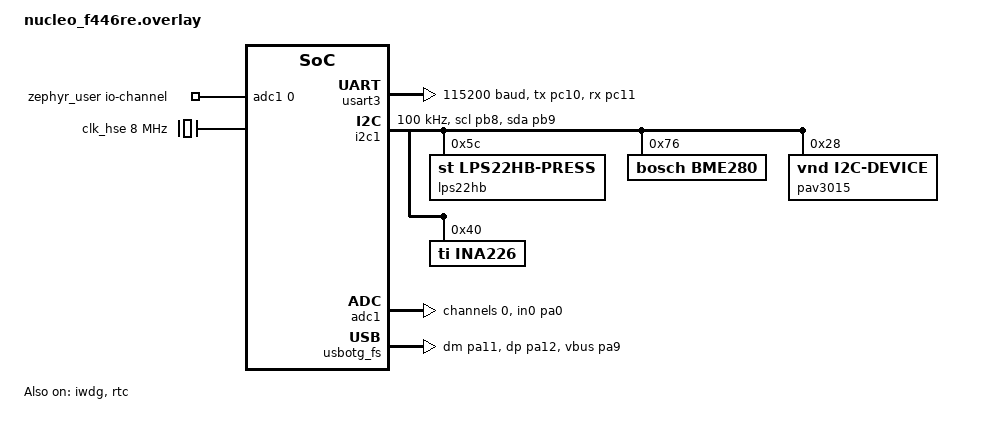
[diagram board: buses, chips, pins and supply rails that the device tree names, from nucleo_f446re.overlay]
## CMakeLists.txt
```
cmake_minimum_required(VERSION 3.20.0)

find_package(Zephyr REQUIRED HINTS $ENV{ZEPHYR_BASE})
project(medical_firmware)

zephyr_cc_option(-Wno-deprecated-declarations -Wno-deprecated)

target_include_directories(app PRIVATE
    include
    include/Power_Management_System
    include/RTOS_Command_based_thread_system
    include/Smart_Battery_System
)

# Sources moved into subfolders
file(GLOB PMS_SRCS      CONFIGURE_DEPENDS ${CMAKE_CURRENT_SOURCE_DIR}/src/Power_Management_System/*.cpp)
file(GLOB BATT_SRCS     CONFIGURE_DEPENDS ${CMAKE_CURRENT_SOURCE_DIR}/src/Smart_Battery_System/*.cpp)
file(GLOB RTOS_CMD_SRCS CONFIGURE_DEPENDS ${CMAKE_CURRENT_SOURCE_DIR}/src/RTOS_Command_based_thread_system/*.cpp)
file(GLOB USB_CDC_SHELL_SRCS CONFIGURE_DEPENDS ${CMAKE_CURRENT_SOURCE_DIR}/src/USB_CDC_SHELL/*.cpp)
file(GLOB FAULT_TOLERANT_I2C_SRCS CONFIGURE_DEPENDS ${CMAKE_CURRENT_SOURCE_DIR}/src/Fault_Tolerant_I2C/*.cpp)

target_sources(app PRIVATE
    src/main.cpp
    ${RTOS_CMD_SRCS}
    src/RTOS_Synchronization_Layer.cpp
    src/Device_State_Machine+Watchdog.cpp
    ${FAULT_TOLERANT_I2C_SRCS}
    src/Persistent_Configuration_System.cpp
    ${PMS_SRCS}
    ${BATT_SRCS}
    src/Static_Memory+MISRA_Compliance_Layer.cpp
    ${USB_CDC_SHELL_SRCS}
)

if(CONFIG_BOARD_MPS2_AN386)
    target_sources(app PRIVATE
        src/qemu_sensor_mocks.c
    )
endif()

target_compile_options(app PRIVATE
    -Wall
    -Wextra
    -Werror
    -Wno-pedantic
    -Wno-variadic-macros
    -Wno-vla
    -Wno-missing-field-initializers
    -Wno-unused-parameter
)

if(CONFIG_COVERAGE)
    target_compile_options(app PRIVATE --coverage -O0)
    target_link_options(app PRIVATE --coverage)
endif()
```

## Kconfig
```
source "Kconfig.zephyr"

config LOG_PREEMPTION_DELAY
    bool "Enable logging for thread pre-emption cycle delays"
    default n
    help
      Enables the LOG_INF statements that print the cycle delay between
      command queue insertion and thread dispatch.

config SOC_MPS2_AN386
    bool
    select HAS_PM
      
config LOG_EXECUTION_CYCLES
    bool "Enable logging for command execution cycle times"
    default n
    help
      Enables the LOG_INF statements inside the CycleProfiler that print
      how many CPU cycles it took to execute a command.
```

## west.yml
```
manifest:
  remotes:
    - name: zephyrproject-rtos
      url-base: https://github.com/zephyrproject-rtos
  projects:
    - name: zephyr
      remote: zephyrproject-rtos
      revision: v4.4.0        # was: main
      import: true
  self:
    path: custom_app
```

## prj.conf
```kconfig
CONFIG_CPP=y
CONFIG_STD_CPP20=y
CONFIG_HEAP_MEM_POOL_SIZE=0
CONFIG_STACK_CANARIES=y

CONFIG_TEST_RANDOM_GENERATOR=y

CONFIG_CONSOLE=y
CONFIG_ASSERT=y
CONFIG_UART_LOG_LEVEL_DBG=y
CONFIG_SHELL_BACKEND_SERIAL=n

CONFIG_PM_DEVICE=y
CONFIG_SHELL=y
CONFIG_SHELL_VT100_COMMANDS=n
CONFIG_FLASH=y
CONFIG_FLASH_MAP=y
CONFIG_FLASH_PAGE_LAYOUT=y
CONFIG_FCB=y
CONFIG_ARM_MPU=y
CONFIG_HW_STACK_PROTECTION=y
CONFIG_MPU_ALLOW_FLASH_WRITE=y

CONFIG_THREAD_NAME=y
CONFIG_THREAD_RUNTIME_STATS=y
CONFIG_TRACING=y
CONFIG_TRACING_USER=y
CONFIG_TRACING_CTF=n
CONFIG_TRACING_BACKEND_UART=n
CONFIG_TRACING_ASYNC=n
CONFIG_TRACING_SYSCALL=n
CONFIG_LOG_BACKEND_FORMAT_TIMESTAMP=y
CONFIG_LOG_BACKEND_SHOW_COLOR=n
CONFIG_LOG_PROCESS_THREAD=y
CONFIG_LOG_MODE_DEFERRED=y
CONFIG_LOG_PROCESS_TRIGGER_THRESHOLD=1
CONFIG_LOG_PROCESS_THREAD_STARTUP_DELAY_MS=0
CONFIG_LOG_PROCESS_THREAD_SLEEP_MS=10

CONFIG_RTC=y
CONFIG_RTC_ALARM=y
CONFIG_LOG=y
CONFIG_LOG_BACKEND_UART=y
CONFIG_PRINTK=y

CONFIG_REQUIRES_FULL_LIBCPP=y
CONFIG_GLIBCXX_LIBCPP=y

CONFIG_WATCHDOG=y
CONFIG_I2C=y
CONFIG_SENSOR=y
CONFIG_REBOOT=y
CONFIG_ADC=y
CONFIG_CBPRINTF_FP_SUPPORT=y
CONFIG_NEWLIB_LIBC=n
CONFIG_NEWLIB_LIBC_MIN_REQUIRED_HEAP_SIZE=0
CONFIG_TIMESLICING=y
CONFIG_LOG_PREEMPTION_DELAY=y
CONFIG_LOG_EXECUTION_CYCLES=n
CONFIG_THREAD_STACK_INFO=y
```

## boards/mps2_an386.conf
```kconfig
# boards/qemu_cortex_m3.conf

# 1. Simulated Flash and NVS
CONFIG_FLASH=y
CONFIG_FLASH_SIMULATOR=y
CONFIG_FLASH_PAGE_LAYOUT=y
CONFIG_FLASH_MAP=y
CONFIG_NVS=y

# 2. General Subsystems
CONFIG_REBOOT=y
CONFIG_COUNTER=y
CONFIG_I2C=y
CONFIG_TEST_RANDOM_GENERATOR=y
CONFIG_WATCHDOG=y

# 3. Standard Console & C++ (Required for QEMU output)
CONFIG_CPP=y
CONFIG_STD_CPP20=y
CONFIG_SERIAL=y
CONFIG_CONSOLE=y
CONFIG_UART_CONSOLE=y
CONFIG_PRINTK=y
CONFIG_LOG_BUFFER_SIZE=4096
CONFIG_LOG_MODE_DEFERRED=y
CONFIG_LOG_PROCESS_THREAD=y
CONFIG_LOG_PROCESS_THREAD_STACK_SIZE=768
CONFIG_ISR_STACK_SIZE=512
CONFIG_SHELL_STACK_SIZE=512
CONFIG_IDLE_STACK_SIZE=128
CONFIG_EMUL=y
CONFIG_I2C_EMUL=y
CONFIG_ADC_EMUL=y
CONFIG_FLASH_SIMULATOR=y
CONFIG_FLASH_SIMULATOR_UNALIGNED_READ=y
CONFIG_INA226=y
CONFIG_SEMIHOST=y
CONFIG_PERCEPIO_TRACERECORDER=y
CONFIG_PERCEPIO_TRC_CFG_STREAM_PORT_RTT=n
CONFIG_PERCEPIO_TRC_CFG_STREAM_PORT_RINGBUFFER=y

CONFIG_LOG_BACKEND_XTENSA_SIM=n 
CONFIG_LOG_TIMESTAMP_64BIT=y
CONFIG_LOG_DEFAULT_LEVEL=3
CONFIG_LOG_BACKEND_UART=y
CONFIG_LOG_PRINTK=n
CONFIG_SYSTEM_WORKQUEUE_STACK_SIZE=384
CONFIG_SYS_CLOCK_TICKS_PER_SEC=1000
```

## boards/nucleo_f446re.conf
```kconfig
CONFIG_USB_CDC_ACM=y
CONFIG_USB_DEVICE_STACK=y
CONFIG_USB_DEVICE_INITIALIZE_AT_BOOT=n
CONFIG_UART_INTERRUPT_DRIVEN=y
CONFIG_UART_LINE_CTRL=y
CONFIG_CBPRINTF_FP_SUPPORT=y

CONFIG_USB_DEVICE_VID=0x0483
CONFIG_USB_DEVICE_PID=0x5740
CONFIG_USB_DEVICE_PRODUCT="Medical Firmware"
CONFIG_USB_DEVICE_MANUFACTURER="STM Microelectronics"
CONFIG_LOG_MODE_IMMEDIATE=n
CONFIG_LOG_BUFFER_SIZE=8192
CONFIG_SENSOR=y
CONFIG_BME280=y
CONFIG_LPS22HB=y
CONFIG_UART_CONSOLE=y

CONFIG_PERCEPIO_TRACERECORDER=n
CONFIG_PERCEPIO_TRC_START_MODE_START=n
CONFIG_PERCEPIO_TRC_CFG_STREAM_PORT_ITM=n
CONFIG_SEGGER_SYSTEMVIEW=n
CONFIG_USE_SEGGER_RTT=y
CONFIG_SEGGER_RTT_BUFFER_SIZE_UP=4096
CONFIG_LOG_BACKEND_SWO=n
CONFIG_SYS_CLOCK_EXISTS=y
CONFIG_STM32_LPTIM_TIMER=y
CONFIG_PM=y
CONFIG_PM_POLICY_DEVICE_CONSTRAINTS=y
CONFIG_SIZE_OPTIMIZATIONS=y
CONFIG_RTC_STM32=y
CONFIG_DEBUG_THREAD_INFO=y
CONFIG_INIT_STACKS=y
CONFIG_STACK_USAGE=y
CONFIG_ISR_STACK_SIZE=4096
CONFIG_COUNTER=n
CONFIG_GPIO=y
CONFIG_IDLE_STACK_SIZE=1024
CONFIG_PM_DEVICE_RUNTIME=n
CONFIG_PM_DEVICE_SYSTEM_MANAGED=n
CONFIG_DEBUG=n
CONFIG_SERIAL=y
CONFIG_ADC_STM32=y
CONFIG_LOG_PRINTK=y
```

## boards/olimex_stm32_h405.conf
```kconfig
# boards/olimex_stm32_h405.conf
# QEMU-safe configuration for olimex_stm32_h405.
# Purpose: run application/RTOS logic without STM32 RCC-dependent hardware drivers.

CONFIG_CPP=y
CONFIG_STD_CPP20=y

# QEMU output is through direct ARM semihosting probe.
CONFIG_SERIAL=n
CONFIG_CONSOLE=n
CONFIG_UART_CONSOLE=n
CONFIG_LOG=n
CONFIG_LOG_BACKEND_UART=n
CONFIG_PRINTK=y
CONFIG_BOOT_BANNER=n

# Disable shell/USB/UART backend paths.
CONFIG_USB_DEVICE_STACK=n
CONFIG_SHELL=n
CONFIG_SHELL_BACKEND_SERIAL=n

# Disable STM32 hardware drivers that depend on RCC/clock-control.
CONFIG_CLOCK_CONTROL=n
CONFIG_GPIO=n
CONFIG_I2C=n
CONFIG_SENSOR=n
CONFIG_WATCHDOG=n
CONFIG_COUNTER=n
CONFIG_COUNTER_RTC_STM32=n
CONFIG_FLASH=n
CONFIG_FLASH_PAGE_LAYOUT=n
CONFIG_NVS=n
CONFIG_PM=n
CONFIG_PM_DEVICE=n

# Disable entropy/RNG path that still tries to use the STM32 clock device.
CONFIG_ENTROPY_GENERATOR=n
CONFIG_ENTROPY_STM32_RNG=n
CONFIG_TEST_RANDOM_GENERATOR=y

CONFIG_REBOOT=y

CONFIG_THREAD_NAME=y
CONFIG_THREAD_ANALYZER=n
CONFIG_THREAD_ANALYZER_AUTO=n
CONFIG_THREAD_ANALYZER_RUN_UNLOCKED=n
CONFIG_RTC=n
```

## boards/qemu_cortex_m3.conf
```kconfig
# boards/qemu_cortex_m3.conf

# 1. Simulated Flash and NVS
CONFIG_FLASH=y
CONFIG_FLASH_SIMULATOR=y
CONFIG_FLASH_PAGE_LAYOUT=y
CONFIG_FLASH_MAP=y
CONFIG_NVS=y

# 2. General Subsystems
CONFIG_REBOOT=y
CONFIG_COUNTER=y
CONFIG_I2C=y
CONFIG_TEST_RANDOM_GENERATOR=y
CONFIG_WATCHDOG=y

# 3. Standard Console & C++ (Required for QEMU output)
CONFIG_CPP=y
CONFIG_STD_CPP20=y
CONFIG_SERIAL=y
CONFIG_CONSOLE=y
CONFIG_UART_CONSOLE=y
CONFIG_PRINTK=y
CONFIG_LOG_BUFFER_SIZE=8192
CONFIG_LOG_MODE_IMMEDIATE=y
CONFIG_HW_STACK_PROTECTION=y
CONFIG_ISR_STACK_SIZE=512
CONFIG_SHELL_STACK_SIZE=1024

CONFIG_SEMIHOST=y
CONFIG_PERCEPIO_TRACERECORDER=y
CONFIG_PERCEPIO_TRC_START_MODE_START=y
CONFIG_PERCEPIO_TRC_CFG_STREAM_PORT_ZEPHYR_SEMIHOST=y

CONFIG_LOG_BACKEND_XTENSA_SIM=n 
```

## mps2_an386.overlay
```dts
#include <zephyr/dt-bindings/adc/adc.h>
/delete-node/ &storage_partition;

/ {
    chosen {
        zephyr,console = &uart0;
    };
    
    zephyr_user: zephyr,user {
        io-channels = <&adc_emul0 0>;
    };

    adc_emul0: adc_emul {
        compatible = "zephyr,adc-emul";
        nchannels = <1>;
        #io-channel-cells = <1>;
        #address-cells = <1>;
        #size-cells = <0>;
        status = "okay";
        ref-internal-mv = <3300>;    
        
        channel@0 {
            reg = <0>;
            zephyr,gain = "ADC_GAIN_1";
            zephyr,reference = "ADC_REF_INTERNAL";
            zephyr,acquisition-time = <ADC_ACQ_TIME_DEFAULT>;
            zephyr,resolution = <12>;
        };
    };
    
    aliases {
        cdc-acm-uart0 = &uart1; 
        watchdog0 = &wdog0;
        rtc0 = &rtc_emul0;
        uart-hardware = &uart0;
        i2c1 = &i2c_emul0;
    };
    
    rtc_emul0: rtc {
        compatible = "zephyr,rtc-emul";
        status = "okay";
        alarms-count = <2>;
    };
    
    /* The Emulator Controller */
    i2c_emul0: i2c_emul@50010000 {
    compatible = "zephyr,i2c-emul-controller";
    reg = <0x50010000 0x1000>;
    clock-frequency = <100000>;
    status = "okay";

    #address-cells = <1>;
    #size-cells = <0>;

    lps22hb: lps22hb@5c {
        compatible = "st,lps22hb-press";
        reg = <0x5c>;
        status = "okay";
    };

    bme280: bme280@76 {
        compatible = "bosch,bme280";
        reg = <0x76>;
        status = "okay";
    };

    ina226: ina226@40 {
        compatible = "ti,ina226";
        reg = <0x40>;
        rshunt-micro-ohms = <100000>;
        current-lsb-microamps = <25>;
        status = "okay";
    };

    pav3015: pav3015@28 {
        compatible = "vnd,i2c-device";
        reg = <0x28>;
        status = "disabled";
    };
    };

    /* Simulated Flash Drive for NVS */
    sim_flash: sim_flash@50000000 {
        compatible = "zephyr,sim-flash";
        /* Expand total simulated flash to 512 KB to fit the Nucleo layout */
        reg = <0x50000000 0x80000>; 
        #address-cells = <1>;
        #size-cells = <1>;
        erase-value = <0xff>;

        my_sim_flash0: flash_sim@0 {
            status = "okay";
            compatible = "soc-nv-flash";
            erase-block-size = <131072>; 
            
            /* CHANGE THIS TO 1: Allows 1-byte and 2-byte FCB writes to succeed */
            write-block-size = <1>; 
            
            reg = <0x00000000 0x80000>;

            partitions {
                compatible = "fixed-partitions";
                #address-cells = <1>;
                #size-cells = <1>;

                code_partition: partition@0 {
                    label = "image-0";
                    reg = <0x00000000 0x00040000>;
                };

                storage_partition: partition@40000 {
                    label = "storage";
                    reg = <0x00040000 0x00040000>;
                };
            };
        };
    };
};
&uart0 {
    status = "okay";
};

&uart1 {
        status = "okay";
};
```

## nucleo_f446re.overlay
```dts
#include <zephyr/dt-bindings/pinctrl/stm32-pinctrl.h>

/ {
    chosen {
        /* Route Zephyr system logs and console to the USB Virtual COM port */
        zephyr,console = &usart3;
        zephyr,shell-uart = &usart3;
        zephyr,code-partition = &code_partition;
        /delete-property/ zephyr,lpm-timer;
        /delete-property/ zephyr,cortex-m-idle-timer;
    };

    aliases {
        cdc-acm-uart0 = &cdc_acm_uart0;
        rtc0 = &rtc;
    };

    zephyr_user: zephyr,user {
        io-channels = <&adc1 0>;
    };

    cpus {
        cpu0: cpu@0 {
            cpu-power-states = <&stop0>;
        };
    };

    power-states {
        stop0: state0 {
            compatible = "zephyr,power-state";
            power-state-name = "suspend-to-ram";
            min-residency-us = <100000>;
            exit-latency-us = <2000>;
        };
    };
};

/* --- DEDICATED SLEEP PIN STATES ---
 * NOTE: the STM32 pinctrl binding requires ONE pinmux value per node.
 * Multi-pin groups are formed by listing several node phandles in
 * pinctrl-N, not by stacking values inside a single node.
 */
&pinctrl {
    /* FIX: Changed from AF7 to strictly ANALOG to prevent UART leakage */
    usart3_tx_sleep: usart3_tx_sleep {
        pinmux = <STM32_PINMUX('C', 10, ANALOG)>;
    };
    usart3_rx_sleep: usart3_rx_sleep {
        pinmux = <STM32_PINMUX('C', 11, ANALOG)>;
    };

    /* FIX: Changed from AF4 to strictly ANALOG to prevent I2C pull-up leakage */
    i2c1_scl_sleep: i2c1_scl_sleep {
        pinmux = <STM32_PINMUX('B', 8, ANALOG)>;
    };
    i2c1_sda_sleep: i2c1_sda_sleep {
        pinmux = <STM32_PINMUX('B', 9, ANALOG)>;
    };

    adc1_in0_sleep: adc1_in0_sleep {
        pinmux = <STM32_PINMUX('A', 0, ANALOG)>;
    };

    usb_otg_fs_vbus_sleep: usb_otg_fs_vbus_sleep {
        pinmux = <STM32_PINMUX('A', 9, ANALOG)>;
    };
};

/* Disable ST-Link UART for Standalone Mode */
&usart3 {
    status = "okay";
    current-speed = <115200>;
    pinctrl-0 = <&usart3_tx_pc10 &usart3_rx_pc11>;
    pinctrl-1 = <&usart3_tx_sleep &usart3_rx_sleep>;
    pinctrl-names = "default", "sleep";
};

/* Explicitly disable unused buses to prevent phantom PM warnings */
&i2c2 { status = "disabled"; };
&i2c3 { status = "disabled"; };

&i2c1 {
    status = "okay";
    pinctrl-0 = <&i2c1_scl_pb8 &i2c1_sda_pb9>;
    pinctrl-1 = <&i2c1_scl_sleep &i2c1_sda_sleep>;
    pinctrl-names = "default", "sleep";
    clock-frequency = <I2C_BITRATE_STANDARD>;

    lps22hb: lps22hb@5c {
        compatible = "st,lps22hb-press";
        reg = <0x5c>;
        status = "okay";
    };
    bme280: bme280@76 {
        compatible = "bosch,bme280";
        reg = <0x76>;
        status = "okay";
    };
    pav3015: pav3015@28 {
        compatible = "vnd,i2c-device";
        reg = <0x28>;
        status = "okay";
    };
    ina226: ina226@40 {
        compatible = "ti,ina226";
        reg = <0x40>;
        rshunt-micro-ohms = <100000>;
        current-lsb-microamps = <25>;
        status = "okay";
    };
};

&adc1 {
    #address-cells = <1>;
    #size-cells = <0>;
    pinctrl-0 = <&adc1_in0_pa0>;
    pinctrl-1 = <&adc1_in0_sleep>;
    pinctrl-names = "default", "sleep";
    st,adc-prescaler = <2>;
    status = "okay";

    channel@0 {
        reg = <0>;
        zephyr,gain = "ADC_GAIN_1";
        zephyr,reference = "ADC_REF_INTERNAL";
        zephyr,acquisition-time = <ADC_ACQ_TIME_DEFAULT>;
        zephyr,resolution = <12>;
    };
};

&gpioa { status = "okay"; };
&gpioc { status = "okay"; };
&iwdg { status = "okay"; };
&usart2 { status = "disabled"; };
&clk_lse { status = "okay"; };

&rtc {
    status = "okay";
    clocks = <&rcc STM32_CLOCK_BUS_APB1 0x10000000>,
             <&rcc STM32_SRC_LSE RTC_SEL(1)>;
    wakeup-source;
};

&clk_hse {
    clock-frequency = <DT_FREQ_M(8)>;
    hse-bypass;
    status = "okay";
};

&pll {
    clocks = <&clk_hse>;
    div-m = <8>;
    mul-n = <384>;
    div-p = <4>;
    div-q = <8>;
    status = "okay";
};

&rcc {
    clocks = <&pll>;
    clock-frequency = <DT_FREQ_M(96)>;
    ahb-prescaler = <1>;
    apb1-prescaler = <4>;
    apb2-prescaler = <2>;
};

&usbotg_fs {
    status = "okay";
    pinctrl-0 = <&usb_otg_fs_dm_pa11 &usb_otg_fs_dp_pa12 &usb_otg_fs_vbus_pa9>;
    /* Only VBUS uses pinctrl sleep. DM/DP left out to allow C++ to force Output Low */
    pinctrl-1 = <&usb_otg_fs_vbus_sleep>;
    pinctrl-names = "default", "sleep";

    cdc_acm_uart0: cdc_acm_uart0 {
        compatible = "zephyr,cdc-acm-uart";
        label = "CDC_ACM_0";
        tx-fifo-size = <2048>;
   	rx-fifo-size = <2048>; 
    };
};

/delete-node/ &boot_partition;
/delete-node/ &slot0_partition;
/delete-node/ &slot1_partition;
/delete-node/ &scratch_partition;
/delete-node/ &storage_partition;

&flash0 {
    partitions {
        compatible = "fixed-partitions";
        #address-cells = <1>;
        #size-cells = <1>;

        code_partition: partition@0 {
            label = "image-0";
            reg = <0x00000000 0x00040000>;
        };

        storage_partition: partition@40000 {
            label = "storage";
            reg = <0x00040000 0x00040000>;
        };
    };
};
```

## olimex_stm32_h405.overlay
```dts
/* olimex_stm32_h405.overlay */

/ {
    chosen {
        zephyr,console = &usart2;
        zephyr,shell-uart = &usart2;
    };

    aliases {
        serial0 = &usart2;

        /*
         * Your USB_CDC_Virtual_COM_Shell_Interface.cpp uses:
         * DEVICE_DT_GET(DT_ALIAS(cdc_acm_uart0))
         *
         * USB is disabled in QEMU, so map this alias to USART2.
         */
        cdc-acm-uart0 = &usart2;
    };
};

/*
 * QEMU-safe clock configuration.
 * Use HSI instead of external HSE/PLL.
 */
&clk_hsi {
    status = "okay";
};

&clk_hse {
    status = "disabled";
};

&pll {
    status = "disabled";
};

&rcc {
    clocks = <&clk_hsi>;
    clock-frequency = <16000000>;
    ahb-prescaler = <1>;
    apb1-prescaler = <1>;
    apb2-prescaler = <1>;
};

&usart2 {
    status = "okay";
    current-speed = <115200>;
    pinctrl-0 = <&usart2_tx_pa2 &usart2_rx_pa3>;
    pinctrl-names = "default";
};

&usbotg_fs {
    status = "disabled";
};

/*
 * Keep I2C enabled in DTS if your full firmware expects i2c1 device.
 * Your I2CManager already mocks reads/writes for CONFIG_BOARD_OLIMEX_STM32_H405.
 */
&i2c1 {
    status = "okay";
    pinctrl-0 = <&i2c1_scl_pb6 &i2c1_sda_pb7>;
    pinctrl-names = "default";
};

&rtc {
    status = "okay";
};

&iwdg {
    status = "okay";
};

/*
 * Required by Persistent_Configuration_System.cpp:
 * DT_NODELABEL(storage_partition)
 */
&flash0 {
    partitions {
        compatible = "fixed-partitions";
        #address-cells = <1>;
        #size-cells = <1>;

        storage_partition: partition@E0000 {
            label = "storage";
            reg = <0x000E0000 0x00020000>;
        };
    };
};

/*
 * QEMU mode:
 * Disable STM32 EXTI and RNG/entropy nodes because they depend on
 * stm32_clock_control_init / RCC, which hangs under olimex-stm32-h405 QEMU.
 */
&exti {
    status = "disabled";
};

&rng {
    status = "disabled";
};
```

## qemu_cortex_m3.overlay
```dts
/ {
    aliases {
        cdc-acm-uart0 = &uart0;
    };

    /* The Golden Stub: We map all missing hardware to the I2C test driver */
    i2c1: fake_i2c@40001000 {
        compatible = "vnd,i2c";
        reg = <0x40001000 0x1000>;
        status = "okay";
        #address-cells = <1>;
        #size-cells = <0>;
    };

    iwdg: fake_watchdog@40002000 {
        compatible = "vnd,i2c";
        reg = <0x40002000 0x1000>;
        status = "okay";
        #address-cells = <1>;
        #size-cells = <0>;
    };

    rtc: fake_rtc@40003000 {
        compatible = "vnd,i2c";
        reg = <0x40003000 0x1000>;
        status = "okay";
        #address-cells = <1>;
        #size-cells = <0>;
    };

    /* Simulated Flash Drive for NVS */
    sim_flash: sim_flash@50000000 {
        compatible = "zephyr,sim-flash";
        reg = <0x50000000 0x8000>;
        #address-cells = <1>;
        #size-cells = <1>;
        erase-value = <0xff>;

        flash_sim0: flash_sim@0 {
            status = "okay";
            compatible = "soc-nv-flash";
            erase-block-size = <1024>;
            write-block-size = <4>;
            reg = <0x00000000 0x8000>;

            partitions {
                compatible = "fixed-partitions";
                #address-cells = <1>;
                #size-cells = <1>;

                storage_partition: partition@6000 {
                    label = "storage";
                    reg = <0x00006000 0x00002000>;
                };
            };
        };
    };
};
```

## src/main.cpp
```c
#include <zephyr/kernel.h>
#include <zephyr/logging/log.h>
#include <zephyr/sys/printk.h>
#ifdef CONFIG_USB_DEVICE_STACK
#include <zephyr/usb/usb_device.h>
#endif
#include <zephyr/drivers/uart.h>
#include <cerrno>

#include "RTOS_Command_Based_Thread_System.h"
#include "RTOS_Synchronization_Layer.h"
#include "Device_State_Machine+Watchdog.h"
#include "Smart_Battery_System.h"
#include "Persistent_Configuration_System.h"
#include "Static_Memory+MISRA_Compliance_Layer.h"
#include "Power_Management_System.h"

#include <zephyr/debug/thread_analyzer.h>
#include <new>
#include <zephyr/sys/atomic.h>

LOG_MODULE_REGISTER(MAIN_OS, LOG_LEVEL_INF);

// Add the external flag at the top with your other externs
extern bool g_usb_connected;

#ifdef CONFIG_USB_DEVICE_STACK
/* Callback to monitor physical USB hardware events */
static void usb_status_cb(enum usb_dc_status_code cb_status, const uint8_t *param) {
    switch (cb_status) {
        case USB_DC_DISCONNECTED:
        case USB_DC_SUSPEND:
            if (g_usb_connected) {
                LOG_WRN("USB Hardware Event: Cable Disconnected");
                g_usb_connected = false;
                
                // Immediately trigger the fault when the physical cable is pulled
                sys_context.triggerFault("USB CDC Cable Disconnected");
            }
            break;
        case USB_DC_CONFIGURED:
            if (!g_usb_connected) {
                LOG_INF("USB Hardware Event: Cable Connected & Configured");
                g_usb_connected = true;
            }
            break;
        default:
            break;
    }
}
#endif

int main(void){
    printk("BOOT\n");
    const struct device *const console_dev  =  DEVICE_DT_GET(DT_CHOSEN(zephyr_console));
    
    if (device_is_ready(console_dev)) {
#ifdef CONFIG_USB_DEVICE_STACK
        /* Initialize USB Subsystem ONCE globally, attaching our new callback */
        int usb_err = usb_enable(usb_status_cb); // Changed from nullptr
        
        if (usb_err == 0 || usb_err == -EALREADY) {
            uint32_t dtr = 0;
            int timeout = 30; // 3 seconds max wait

            while (!dtr && timeout > 0) {
                // If the hardware callback fired and marked us unplugged, skip the wait
                if (!g_usb_connected) break; 
                
                int ret = uart_line_ctrl_get(console_dev, UART_LINE_CTRL_DTR, &dtr);
                if (ret == -ENOTSUP || ret == -ENOSYS) break; 
                
                k_msleep(100);
                timeout--;
            }
            
            if (dtr) k_msleep(250); 
        } else {
            LOG_ERR("Failed to initialize USB subsystem (err %d)", usb_err);
        }
#endif
    }

    LOG_INF("Command-Based RTOS Booting");

    ConfigStore& config = ConfigStore::getInstance();
    if (config.init()) {
        config.validateEndurance(ConfigKey::ALARM_THRESHOLD_BASE);
        uint16_t infusion_rate = 0;
        if (!config.get(ConfigKey::INFUSION_RATE_BASE, infusion_rate)) {
            LOG_WRN("First boot detected. Setting default infusion rate.");
            config.set(ConfigKey::INFUSION_RATE_BASE, static_cast<uint16_t>(50));
        } else {
            LOG_INF("Loaded Infusion Rate from NVS: %u mL/hr", infusion_rate);
        }
    }
    
    status_work.schedule(K_SECONDS(1));
    return 0;
}
```

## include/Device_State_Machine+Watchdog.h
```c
#pragma once
#include <zephyr/kernel.h>
#include <zephyr/drivers/watchdog.h>
#include "Power_Management_System.h"
/* Global Thread Health Flags (Updated by ALL RTOS Threads) */
extern atomic_t g_producer_alive;
extern atomic_t g_processor_alive;
extern atomic_t g_logger_alive;
extern atomic_t g_hr_prod_alive;
extern atomic_t g_disp_cons_alive;
extern atomic_t g_bms_comm_alive;
extern atomic_t g_batt_mon_alive;
extern atomic_t g_mem_mon_alive;
extern atomic_t g_shell_alive;
extern DeviceContext sys_context;

enum class SystemState {
  INIT,
  RUNNING,
  FAULT,
  SAFE_HALT
};

class WatchdogTimer {
    private:
        const device* wdt_dev;
        int channel_id;
    public:
        WatchdogTimer();
        bool init(uint32_t timeout_ms);
        void feed();
        bool isInitialized() const;
};

class DeviceContext : public IPowerObserver {
    private:
        SystemState current_state;
        WatchdogTimer wdt;
        static bool isLegalTransition(SystemState from, SystemState to);
    public:
        DeviceContext();
        SystemState getState() const;
        bool requestTransition(SystemState next_state);
        bool initWatchdog(uint32_t timeout_ms);
        void feedWatchdog();
        void triggerFault(const char* reason);
        void beforeSleep() override;
        void afterWakeup() override;
        void sleepAborted() override;
};
```

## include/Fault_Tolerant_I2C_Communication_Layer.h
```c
#include <zephyr/drivers/i2c.h>
#include <cstdint>
#include "Static_Memory+MISRA_Compliance_Layer.h"

#pragma once

enum class I2CFault{NONE,NACK,TIMEOUT,BUS_BUSY,ARBITRATION_LOST,DEVICE_NOT_READY};

template <typename T>
struct Result{
    T value;
    I2CFault error;
    bool success;

    static Result<T> Ok(T val){
        return {val,I2CFault::NONE,true};
    }

    static Result<T> Err(I2CFault err){
        return {T(),err,false};
    }

    bool isOk() const {return success; }
    T unwrap() const{ return value; }
};

class I2CStrategy{
  public:
        virtual ~I2CStrategy()=default;
        virtual void executeRecovery(const device* i2c_dev)=0;
};

class RetryStrategy:public I2CStrategy{
  public:
      void executeRecovery(const device* i2c_dev) override;
};

class BusResetStrategy:public I2CStrategy{
  public:
      void executeRecovery(const device* i2c_dev) override;
};

class FailSafeStrategy:public I2CStrategy{
  private:
      uint64_t last_known_good_value=0U;
  public:
      void executeRecovery(const device* i2c_dev) override;
      void updateLastGood(uint64_t val);
      uint64_t getLastGood() const;
};

class I2CManager{
  private:
      const device* i2c_dev;
      RetryStrategy retry_strategy;
      BusResetStrategy reset_strategy;
      FailSafeStrategy failsafe_strategy;
  public:
      explicit I2CManager(const device* dev);
      Result<uint8_t> readRegister(uint16_t sensor_addr,uint8_t reg_addr);
      Result<bool> writeRegister(uint16_t sensor_addr,uint8_t reg_addr,uint8_t val);
      Result<uint16_t> readWord(uint16_t sensor_addr,uint8_t reg_addr);
      Result<bool> writeWord(uint16_t sensor_addr, uint8_t reg_addr, uint16_t val);
      Result<uint32_t> read24Bit(uint16_t sensor_addr,uint8_t reg_addr);
      Result<uint64_t> read64Bit(uint16_t sensor_addr,uint8_t reg_addr);
};

extern I2CManager i2c_manager;
```

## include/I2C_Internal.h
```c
#pragma once

#include <cstdint>
#include "Fault_Tolerant_I2C_Communication_Layer.h"

#ifdef IS_TEST_ENVIRONMENT
extern int g_i2c_force_errno;
#endif

namespace i2c_internal {

/* Map a negative Zephyr driver errno to an I2CFault enum value. */
I2CFault classify_i2c_error(int err);

/* Return true when the fault requires a physical SCL bus reset (TIMEOUT or BUS_BUSY). */
bool is_recoverable_with_bus_reset(I2CFault fault);

/* Classify `err` and execute either `reset_strategy` or `retry_strategy`. */
I2CFault classify_and_recover(int err,
                              const device* i2c_dev,
                              BusResetStrategy& reset_strategy,
                              RetryStrategy& retry_strategy);

/* Store / refresh the value for `key`: resets the reliability score to the maximum, bumps the sample count. */
void update_cache(uint32_t key, uint64_t value, bool calibrated = true);

/* Fallback read: succeeds only for a fresh (<= max_age_ms), reliable (score >= minimum) and calibrated entry,
 * and decays the entry's reliability on every successful use. */
bool get_cached_value(uint32_t key, uint64_t* out_val, uint32_t max_age_ms);

} // namespace i2c_internal
```

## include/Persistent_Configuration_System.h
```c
#pragma once

#include <zephyr/fs/fcb.h>
#include <zephyr/logging/log.h>
#include <zephyr/pm/policy.h>
#include "Power_Management_System.h"
#include <type_traits>
#include <cstdint>
#include <array>

enum class ConfigKey : uint16_t {
    FULL_CHARGE_LOG        = 4,
    DEVICE_ID_BASE         = 100,
    INFUSION_RATE_BASE     = 200,
    ALARM_THRESHOLD_BASE   = 300
};

namespace InfusionDeviceConfig {
    constexpr uint8_t MinSlot = 1;
    constexpr uint8_t MaxSlot = 5;
    constexpr uint8_t NumSlots = 5;

    constexpr uint32_t UnprovisionedId = 0;

    constexpr std::array<uint32_t, NumSlots> DefaultDeviceIds        = {1001, 1002, 1003, 1004, 1005};
    constexpr std::array<uint8_t,  NumSlots> DefaultAlarmThresholds  = {80, 85, 90, 95, 100};

    [[nodiscard]] constexpr bool isValidSlot(uint8_t slot) noexcept {
        return slot >= MinSlot && slot <= MaxSlot;
    }
}

class FlashPowerGuard {
public:
    FlashPowerGuard() {
        pm_policy_state_lock_get(PM_STATE_SUSPEND_TO_RAM, PM_ALL_SUBSTATES);
    }
    ~FlashPowerGuard() {
        pm_policy_state_lock_put(PM_STATE_SUSPEND_TO_RAM, PM_ALL_SUBSTATES);
    }
};

struct FcbRecordHeader {
    ConfigKey key;
    uint16_t length;
};

class ConfigStore {
    private:
        struct fcb fcb_instance;
        struct flash_sector fcb_sectors[2]; // Sectors 6 and 7
        bool initialized;

        static ConfigStore instance;

        ConfigStore();
        ~ConfigStore()=default;

        ConfigStore(const ConfigStore&)=delete;
        ConfigStore& operator=(const ConfigStore&)=delete;

        void seedDefaultDeviceIds();
        void seedDefaultAlarmThresholds();

    public:
        static ConfigStore& getInstance();

        bool init();

        template <typename T>
        bool set(ConfigKey key, const T& value) {
            static_assert(std::is_trivially_copyable<T>::value, "Config data must be trivially copyable");

            if (!initialized){
                return false;
            }

            FlashPowerGuard pm_guard;

            struct fcb_entry loc;
            int rc = fcb_append(&fcb_instance, sizeof(FcbRecordHeader) + sizeof(T), &loc);
            if (rc == -ENOSPC) {
                // Flash area full: rotate (erase oldest sector) and retry once.
                rc = fcb_rotate(&fcb_instance);
                if (rc != 0) {
                    return false;
                }
                rc = fcb_append(&fcb_instance, sizeof(FcbRecordHeader) + sizeof(T), &loc);
            }
            if (rc != 0) {
                return false;
            }

            FcbRecordHeader header = { key, sizeof(T) };
            rc = flash_area_write(fcb_instance.fap, FCB_ENTRY_FA_DATA_OFF(loc), &header, sizeof(header));
            if (rc != 0) return false;

            rc = flash_area_write(fcb_instance.fap, FCB_ENTRY_FA_DATA_OFF(loc) + sizeof(header), &value, sizeof(T));
            if (rc != 0) return false;

            fcb_append_finish(&fcb_instance, &loc);
            PowerManager::getInstance().reportActivity();
            return true;
        }

        template <typename T>
        bool get(ConfigKey key, T& out_value) {
            static_assert(std::is_trivially_copyable<T>::value, "Config data must be trivially copyable.");

            if (!initialized){
                return false;
            }

            struct fcb_entry loc;
            loc.fe_sector = nullptr;
            loc.fe_elem_off = 0;

            bool found = false;
            FcbRecordHeader header;
            T temp_val;

            // Walk through all records to find the most recent one for this key
            while (fcb_getnext(&fcb_instance, &loc) == 0) {
                flash_area_read(fcb_instance.fap, FCB_ENTRY_FA_DATA_OFF(loc), &header, sizeof(header));
                
                if (header.key == key && header.length == sizeof(T)) {
                    flash_area_read(fcb_instance.fap, FCB_ENTRY_FA_DATA_OFF(loc) + sizeof(header), &temp_val, sizeof(T));
                    found = true;
                }
            }

            if (found) {
                out_value = temp_val;
            }
            return found;
        }

        bool validateEndurance(ConfigKey key);

        [[nodiscard]] bool setDeviceId(uint8_t slot, uint32_t deviceId){
            if (!InfusionDeviceConfig::isValidSlot(slot)){
                return false;
            }
            return set(static_cast<ConfigKey>(static_cast<uint16_t>(ConfigKey::DEVICE_ID_BASE) + slot), deviceId);
        }

        [[nodiscard]] bool getDeviceId(uint8_t slot, uint32_t& out){
            if (!InfusionDeviceConfig::isValidSlot(slot)){
                return false;
            }
            return get(static_cast<ConfigKey>(static_cast<uint16_t>(ConfigKey::DEVICE_ID_BASE) + slot), out);
        }

        [[nodiscard]] bool findSlotByDeviceId(uint32_t deviceId, uint8_t& out_slot){
            for (uint8_t slot = InfusionDeviceConfig::MinSlot; slot <= InfusionDeviceConfig::MaxSlot; ++slot){
                uint32_t stored = InfusionDeviceConfig::UnprovisionedId;
                if (getDeviceId(slot, stored) && stored == deviceId){
                    out_slot = slot;
                    return true;
                }
            }
            return false;
        }

        [[nodiscard]] bool setInfusionRate(uint8_t slot, uint8_t rate){
            if (!InfusionDeviceConfig::isValidSlot(slot) || rate < 1 || rate > 100){
                return false;
            }
            return set(static_cast<ConfigKey>(static_cast<uint16_t>(ConfigKey::INFUSION_RATE_BASE) + slot), rate);
        }

        [[nodiscard]] bool getInfusionRate(uint8_t slot, uint8_t& out){
            if (!InfusionDeviceConfig::isValidSlot(slot)){
                return false;
            }
            return get(static_cast<ConfigKey>(static_cast<uint16_t>(ConfigKey::INFUSION_RATE_BASE) + slot), out);
        }

        [[nodiscard]] bool setAlarmThreshold(uint8_t slot, uint8_t threshold){
            if (!InfusionDeviceConfig::isValidSlot(slot) || threshold < 80 || threshold > 100){
                return false;
            }
            return set(static_cast<ConfigKey>(static_cast<uint16_t>(ConfigKey::ALARM_THRESHOLD_BASE) + slot), threshold);
        }

        [[nodiscard]] bool getAlarmThreshold(uint8_t slot, uint8_t& out){
            if (!InfusionDeviceConfig::isValidSlot(slot)){
                return false;
            }
            return get(static_cast<ConfigKey>(static_cast<uint16_t>(ConfigKey::ALARM_THRESHOLD_BASE) + slot), out);
        }
        
        struct LogEntry {
        uint32_t timestamp_ms;
        uint8_t event_id; // e.g., 0x01 = Battery Full, 0x02 = Fault, 0x03 = State Change
        int32_t event_data;
    };

    // New methods required for the USB Shell
    [[nodiscard]] uint32_t getStoredLogCount() const noexcept;
    [[nodiscard]] bool getLogEntry(uint32_t index, LogEntry& out_entry) const noexcept;
};
```

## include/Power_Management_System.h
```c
#pragma once

#include <zephyr/kernel.h>
#include <zephyr/device.h>
#include <cstdint>
#include <atomic>
#include <array>
#include <zephyr/sys/atomic.h>

constexpr size_t MAX_OBSERVERS = 8;
constexpr uint8_t PM_FAILURE_FAULT_THRESHOLD = 3;
class PowerManager;
class DeviceContext;
extern bool s_real_hw_sleep_active;
extern uint32_t s_elapsed_sleep_time_us;
extern uint32_t s_current_sleep_interval_us;

enum class StopWakeReason : uint8_t {
    WAKE_NONE,
    WAKE_RTC,
    WAKE_ACTIVITY,
    WAKE_UNKNOWN,
    WAKE_ABORTED
};

extern atomic_t s_activity_pending;
extern volatile StopWakeReason s_stop_wake_reason;
extern struct k_sem pm_wake_sem;
extern struct k_sem stop_wake_sem;
void advance_rtc_time(struct rtc_time& time, uint32_t seconds_to_add);
bool clear_rtc_alarm_a_pending();
int set_rtc_alarm(const struct device* rtc_dev, uint32_t interval_us, void* user_data);
void clear_rtc_alarm(const struct device* rtc_dev);
extern const k_tid_t processor_tid;
extern const k_tid_t producer_tid;
extern const k_tid_t logger_tid;
extern const k_tid_t battery_tid;
extern const k_tid_t shell_tid;
extern const k_tid_t bms_comm_tid;
extern const k_tid_t hr_prod_tid;
extern const k_tid_t disp_cons_tid;
extern const k_tid_t mem_mon_tid;
extern const k_tid_t trace_tid;

class IPowerObserver {
public:
    virtual ~IPowerObserver() = default;
    virtual void beforeSleep() = 0;
    virtual void afterWakeup() = 0;
    virtual void sleepAborted() = 0;
};

class IPowerState {
public:
    virtual ~IPowerState() = default;
    
    virtual bool enter(PowerManager& pm) = 0;
    virtual IPowerState& execute(PowerManager& pm) = 0;
    virtual void exit(PowerManager& pm) = 0;
    
    virtual const char* getName() const = 0;
};

class PowerManager {
public:
    static PowerManager& getInstance();

    bool init(const struct device* rtc, const struct device* i2c, 
              const struct device* uart, const struct device* usb, 
              const struct device* adc, DeviceContext* fault_ctx);

    bool registerObserver(IPowerObserver* obs);
    void reportActivity();
    void reportPmFailure();
    void processFSM();

    // Notifiers for observers
    void notifyBeforeSleep();
    void notifyAfterWakeup();
    void notifySleepAborted();

    // Getters and Setters used by concrete states
    uint32_t getLastActivityTime() const { return last_activity_time.load(); }
    void clearWakePending() { atomic_set(&wake_pending, 0); }
    
    // Consumes the wake flag atomically to prevent race conditions during STOP mode wake
    bool consumeWakePending(); 
    
    const struct device* getRtcDev() const { return rtc_dev; }
    const struct device* getI2cDev() const { return i2c_dev; }
    const struct device* getUartDev() const { return uart_dev; }
    const struct device* getUsbDev() const { return usb_dev; }
    const struct device* getAdcDev() const { return adc_dev; }

    void recordSleepTime() { last_sleep_time = k_uptime_get_32(); }
    void setExpectedWakeTime(uint32_t time) { expected_wake_time = time; }
    uint32_t getSleepTime() const { return last_sleep_time; }
    uint32_t getExpectedWakeTime() const { return expected_wake_time; }
    
    void resetPmFailures() { consecutive_pm_failures = 0; }

    // Static callback for RTC API
    static void rtc_alarm_handler(const struct device* dev, uint16_t id, void* user_data);

#ifdef IS_TEST_ENVIRONMENT
    void resetForTest();
#endif

    // Exposed for direct alarm manipulation in states
    atomic_t wake_pending;

private:
    PowerManager();
    ~PowerManager() = default;
    PowerManager(const PowerManager&) = delete;
    PowerManager& operator=(const PowerManager&) = delete;

    void transitionTo(IPowerState& next_state);
    size_t captureObservers(std::array<IPowerObserver*, MAX_OBSERVERS>& out);

    IPowerState* current_state;
    
    uint32_t last_sleep_time;
    uint32_t expected_wake_time;

    const struct device* rtc_dev;
    const struct device* i2c_dev;
    const struct device* uart_dev;
    const struct device* usb_dev;
    const struct device* adc_dev;

    size_t observer_count;
    std::array<IPowerObserver*, MAX_OBSERVERS> observers;
    
    DeviceContext* fault_context;
    uint32_t consecutive_pm_failures;

    std::atomic<uint32_t> last_activity_time;
};

class ActiveState : public IPowerState {
public:
    static ActiveState& getInstance();
    bool enter(PowerManager& pm) override;
    IPowerState& execute(PowerManager& pm) override;
    void exit(PowerManager& pm) override;
    const char* getName() const override { return "PM_STATE_ACTIVE"; }

private:
    ActiveState() = default;
};

class IdleState : public IPowerState {
public:
    static IdleState& getInstance();
    bool enter(PowerManager& pm) override;
    IPowerState& execute(PowerManager& pm) override;
    void exit(PowerManager& pm) override;
    const char* getName() const override { return "PM_STATE_SUSPEND_TO_IDLE"; }

private:
    IdleState() = default;
};

class StopState : public IPowerState {
public:
    static StopState& getInstance();
    bool enter(PowerManager& pm) override;
    IPowerState& execute(PowerManager& pm) override;
    void exit(PowerManager& pm) override;
    const char* getName() const override { return "PM_STATE_SUSPEND_TO_RAM"; }

#ifdef IS_TEST_ENVIRONMENT
    void resetForTest() { sleep_prepared = false; }
#endif

private:
    StopState() = default;
    bool sleep_prepared = false;
};
```

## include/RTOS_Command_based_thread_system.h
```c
#pragma once

#include <zephyr/kernel.h>
#include <cstdint>
#include <utility>
#include "Fault_Tolerant_I2C_Communication_Layer.h"
#include "Device_State_Machine+Watchdog.h"
#include "Power_Management_System.h"

namespace QueueConfig {
    constexpr size_t Depth = 10;
    constexpr size_t Alignment = 4;
}

namespace PoolConfig {
    constexpr size_t Elements = 16;
    constexpr size_t Size = 48;
}

namespace ThreadConfig {
    constexpr size_t StackSmall = 512;
    constexpr size_t StackLarge = 1024;
    constexpr int PrioProducer  = 6;
    constexpr int PrioProcessor = 5;
    constexpr int PrioLogger    = 4;
}

enum class SensorID : uint16_t {
    BME280       = 0x76,
    BME280_PRESS = 0x176,
    BME280_HUM   = 0x276,
    LPS22HB      = 0x5C,
    LPS22HB_TEMP = 0x15C,
    PAV3015      = 0x28
};

enum class ReadLength : uint8_t {
    Word   = 2,
    Triple = 3,
    Block  = 8
};

enum class ProducerState : uint8_t {
    ReadBME,
    ReadLPS,
    ReadPAV
};

static_assert(sizeof(SensorID) == 2, "SensorID must be 16-bit");
static_assert(sizeof(ReadLength) == 1, "ReadLength must be 8-bit");
static_assert(QueueConfig::Depth > 0, "Queue depth must be greater than 0");
static_assert(PoolConfig::Elements >= QueueConfig::Depth, "Pool must support peak queue depth");
static_assert(ThreadConfig::PrioProcessor < ThreadConfig::PrioProducer, "Processor must have higher priority than Producer to prevent starvation");

namespace LogTags {
    constexpr char READ[]     = "READ";
    constexpr char COMPUTE[]  = "COMPUTE";
    constexpr char PRINT[]    = "PRINT";
    constexpr char PRODUCER[] = "PRODUCER";
}

struct SensorDescriptor {
    SensorID id;
    uint8_t reg;
    ReadLength len;
};

namespace SensorReg {
    constexpr uint8_t BME280_CTRL_HUM   = 0xF2;
    constexpr uint8_t BME280_CTRL_MEAS  = 0xF4;
    constexpr uint8_t BME280_DATA_START = 0xF7;
    constexpr SensorDescriptor BME_DESC = { SensorID::BME280, 0xF7, ReadLength::Block };

    constexpr SensorDescriptor LPS_P_DESC = { SensorID::LPS22HB, 0x28, ReadLength::Triple };
    constexpr SensorDescriptor LPS_T_DESC = { SensorID::LPS22HB, 0x2B, ReadLength::Word };

    constexpr SensorDescriptor PAV_DESC = { SensorID::PAV3015, 0x00, ReadLength::Word };
}

namespace BME280CalibReg {
    constexpr uint8_t DIG_T1 = 0x88; constexpr uint8_t DIG_T2 = 0x8A; constexpr uint8_t DIG_T3 = 0x8C;
    constexpr uint8_t DIG_P1 = 0x8E; constexpr uint8_t DIG_P2 = 0x90; constexpr uint8_t DIG_P3 = 0x92;
    constexpr uint8_t DIG_P4 = 0x94; constexpr uint8_t DIG_P5 = 0x96; constexpr uint8_t DIG_P6 = 0x98;
    constexpr uint8_t DIG_P7 = 0x9A; constexpr uint8_t DIG_P8 = 0x9C; constexpr uint8_t DIG_P9 = 0x9E;
    constexpr uint8_t DIG_H1 = 0xA1; constexpr uint8_t DIG_H2_L = 0xE1; constexpr uint8_t DIG_H2_M = 0xE2;
    constexpr uint8_t DIG_H3 = 0xE3; constexpr uint8_t DIG_H4_M = 0xE4; constexpr uint8_t DIG_H_SHARED = 0xE5;
    constexpr uint8_t DIG_H5_M = 0xE6; constexpr uint8_t DIG_H6 = 0xE7;
}

namespace BME280Config {
    constexpr uint8_t CTRL_HUM = 0x01;
    constexpr uint8_t CTRL_MEAS = 0x27;
}

namespace MockValues {
    constexpr uint16_t STEP = 17;
    constexpr uint64_t BME_P_BASE = 512000ULL;
    constexpr uint64_t BME_T_BASE = 512000ULL;
    constexpr uint64_t BME_H_BASE = 25000ULL;
    constexpr uint64_t LPS_P_BASE = 4000000ULL;
    constexpr uint64_t LPS_T_BASE = 2500ULL;
    constexpr uint64_t PAV_BASE   = 409ULL;
}

struct alignas(4) BME280Calibration {
    bool is_loaded = false;
    uint16_t dig_T1; int16_t dig_T2; int16_t dig_T3;
    uint16_t dig_P1; int16_t dig_P2; int16_t dig_P3;
    int16_t dig_P4;  int16_t dig_P5; int16_t dig_P6;
    int16_t dig_P7;  int16_t dig_P8; int16_t dig_P9;
    uint8_t  dig_H1; int16_t dig_H2; uint8_t  dig_H3;
    int16_t  dig_H4; int16_t dig_H5; int8_t   dig_H6;
};

struct BME280Data {
    float temperature;
    float pressure;
    float humidity;
};

struct LPS22HBData {
    float temperature;
    float pressure;
};

namespace BME280Math {
    [[nodiscard]] BME280Data decode(uint64_t raw_data, const BME280Calibration& calib) noexcept;
}

namespace LPS22HBMath {
    [[nodiscard]] float decodeTemperature(uint64_t raw) noexcept;
    [[nodiscard]] float decodePressure(uint64_t raw) noexcept;
}

namespace PAV3015Math {
    [[nodiscard]] float decodeAirflow(uint64_t raw) noexcept;
}

class ICommand {
public:
    uint32_t command_id;

    ICommand();
    virtual ~ICommand() = default;

    ICommand(const ICommand&) = delete;
    ICommand& operator=(const ICommand&) = delete;
    ICommand(ICommand&&) = delete;
    ICommand& operator=(ICommand&&) = delete;

    virtual void execute() noexcept = 0;

    void operator delete(void* ptr) noexcept;
    void destroy() noexcept;
};

class SensorReadCmd final : public ICommand {
private:
    SensorID sensor_id;
    uint8_t reg_addr;
    ReadLength length;

    [[nodiscard]] Result<uint64_t> readHardwareData() const noexcept;
    [[nodiscard]] uint64_t readMockPAVData() const noexcept;

public:
    SensorReadCmd(SensorID s_id, uint8_t r_addr, ReadLength len) noexcept;
    void execute() noexcept override final;
};

class ComputeCmd final : public ICommand {
private:
    SensorID sensor_id;
    uint8_t reg_addr;
    uint64_t raw_data;

public:
    ComputeCmd(SensorID s_id, uint8_t r_addr, uint64_t data) noexcept;
    void execute() noexcept override final;
};

class PrintCmd final : public ICommand {
private:
    SensorID sensor_id;
    float final_value;

    [[nodiscard]] const char* getSensorName() const noexcept;

public:
    PrintCmd(SensorID s_id, float val) noexcept;
    void execute() noexcept override final;
};

class PrintBME280Cmd final : public ICommand {
private:
    BME280Data data;

public:
    explicit PrintBME280Cmd(const BME280Data& d) noexcept;
    void execute() noexcept override final;
};

class PrintLPS22HBCmd final : public ICommand {
private:
    LPS22HBData data;

public:
    explicit PrintLPS22HBCmd(const LPS22HBData& d) noexcept;
    void execute() noexcept override final;
};

[[nodiscard]] bool printBME280Measurement(const BME280Data& data) noexcept;

[[nodiscard]] bool printLPS22HBMeasurement(const LPS22HBData& data) noexcept;

struct QueueStats {
    uint32_t commandsCreated = 0;
    uint32_t commandsDropped = 0;
    uint32_t loggerQueueFull = 0;
    uint32_t processorPeakDepth = 0;
    uint32_t loggerPeakDepth = 0;
};
extern QueueStats g_queueStats;

namespace SystemObjects {
    DeviceContext& context();
    I2CManager& i2c();
    PowerManager& power();
}

extern struct k_msgq processor_queue;
extern struct k_msgq logger_queue;

constexpr auto PROCESSOR_Q = &processor_queue;
constexpr auto LOGGER_Q    = &logger_queue;

void* allocateCommandMemory() noexcept;
bool enqueueCommandRaw(k_msgq* queue, ICommand* cmd) noexcept;

template<typename CmdType, typename... Args>
[[nodiscard]] bool enqueueCommand(k_msgq* queue, Args&&... args) noexcept {
    void* mem = allocateCommandMemory();
    if (!mem) return false;
    ICommand* cmd = new(mem) CmdType(std::forward<Args>(args)...);
    if (!enqueueCommandRaw(queue, cmd)) {
        cmd->destroy();
        return false;
    }
    return true;
}

[[nodiscard]] bool printMeasurement(SensorID id, float value) noexcept;

void producer_thread(void);
void processor_thread(void);
void logger_thread(void);

extern const k_tid_t producer_tid;
extern const k_tid_t processor_tid;
extern const k_tid_t logger_tid;
```

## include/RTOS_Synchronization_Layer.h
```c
#pragma once
#include <zephyr/kernel.h>
#include <array>
#include <cstdint>

class ZephyrSemaphore {
  private:
      k_sem sem;
  public:
    ZephyrSemaphore(unsigned int initial,unsigned int limit);
    void give();
    int take(k_timeout_t timeout);
};

class ZephyrMutex{
  private:
      k_mutex mutex;
  public:
      ZephyrMutex();
      void lock();
      void unlock();
};

class ZephyrWorkQueue {
  private:
      k_work_delayable work;
      void (*callback)();
      static void execute_callback(struct k_work *w);
  public:
      explicit ZephyrWorkQueue(void (*cb)());
      void schedule(k_timeout_t delay);
      void cancel();
};

struct SharedHeartRateBuffer{
      std::array<uint32_t,10> data;
      size_t head=0;
      size_t tail=0;
      ZephyrMutex mutex;
};
extern SharedHeartRateBuffer hr_buffer;
extern ZephyrSemaphore display_sem;
extern ZephyrWorkQueue status_work;
```

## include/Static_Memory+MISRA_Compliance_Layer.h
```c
#include <array>
#include <cstdint>
#include <new>
#include <cstddef>
#include <zephyr/kernel.h>
#include <zephyr/logging/log.h>
#pragma once

template <typename T,size_t N>
class StaticPool{
    private:
        alignas(4) std::array<uint8_t,sizeof(T)*N> memory_block;
        std::array<bool,N> in_use;
        k_mutex pool_mutex;

    public:
        StaticPool(){
            in_use.fill(false);
            k_mutex_init(&pool_mutex);
        }

        void* allocate(){
            k_mutex_lock(&pool_mutex,K_FOREVER);
            void* ptr=nullptr;

            for (size_t i=0;i<N;i++){
                if(!in_use[i]){
                    in_use[i]=true;
                    ptr=&memory_block[i*sizeof(T)];
                    break;
                }
            }
            k_mutex_unlock(&pool_mutex);

            if (ptr==nullptr){
                printk("[ERR] StaticPool Out of Memory! Pool Size: %zu\n", N);
            }
            return ptr;
        }

        void deallocate(void* ptr){
            if (ptr==nullptr){
                return;
            }

            k_mutex_lock(&pool_mutex,K_FOREVER);
            auto* byte_ptr=static_cast<uint8_t*>(ptr);
            auto* base_ptr=memory_block.data();

            if (byte_ptr>=base_ptr && byte_ptr<base_ptr+(sizeof(T)*N)){
                size_t index=(byte_ptr-base_ptr)/sizeof(T);
                in_use[index]=false;
            }
            else{
                printk("[ERR] Invalid pointer passed to deallocate\n");
            }
            k_mutex_unlock(&pool_mutex);
        }
    };
```
